# SPDX-FileCopyrightText: 2026 Harald Pretl, Johannes Kepler University
# SPDX-License-Identifier: Apache-2.0 WITH SHL-2.1
# Generated by ip/ez130_8t_decap_hv/scripts/decap_hv_gen.py -- do not edit.

VERSION 5.8 ;
BUSBITCHARS "[]" ;
DIVIDERCHAR "/" ;

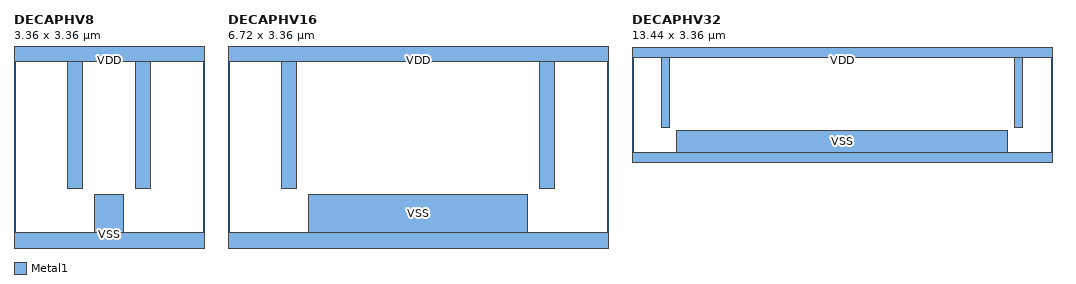
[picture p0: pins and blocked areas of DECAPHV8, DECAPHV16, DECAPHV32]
MACRO DECAPHV8
  CLASS CORE SPACER ;
  ORIGIN 0 0 ;
  FOREIGN DECAPHV8 0 0 ;
  SIZE 3.36 BY 3.36 ;
  SYMMETRY X Y ;
  SITE CoreSite ;
  PIN VDD
    DIRECTION INOUT ;
    USE POWER ;
    SHAPE ABUTMENT ;
    PORT
      LAYER Metal1 ;
        RECT 0 3.2 3.36 3.52 ;
        RECT 0.95 0.95 1.21 3.2 ;
        RECT 2.15 0.95 2.41 3.2 ;
    END
  END VDD
  PIN VSS
    DIRECTION INOUT ;
    USE GROUND ;
    SHAPE ABUTMENT ;
    PORT
      LAYER Metal1 ;
        RECT 0 -0.16 3.36 0.16 ;
        RECT 1.43 0.16 1.93 0.84 ;
    END
  END VSS
END DECAPHV8

MACRO DECAPHV16
  CLASS CORE SPACER ;
  ORIGIN 0 0 ;
  FOREIGN DECAPHV16 0 0 ;
  SIZE 6.72 BY 3.36 ;
  SYMMETRY X Y ;
  SITE CoreSite ;
  PIN VDD
    DIRECTION INOUT ;
    USE POWER ;
    SHAPE ABUTMENT ;
    PORT
      LAYER Metal1 ;
        RECT 0 3.2 6.72 3.52 ;
        RECT 0.95 0.95 1.21 3.2 ;
        RECT 5.51 0.95 5.77 3.2 ;
    END
  END VDD
  PIN VSS
    DIRECTION INOUT ;
    USE GROUND ;
    SHAPE ABUTMENT ;
    PORT
      LAYER Metal1 ;
        RECT 0 -0.16 6.72 0.16 ;
        RECT 1.43 0.16 5.29 0.84 ;
    END
  END VSS
END DECAPHV16

MACRO DECAPHV32
  CLASS CORE SPACER ;
  ORIGIN 0 0 ;
  FOREIGN DECAPHV32 0 0 ;
  SIZE 13.44 BY 3.36 ;
  SYMMETRY X Y ;
  SITE CoreSite ;
  PIN VDD
    DIRECTION INOUT ;
    USE POWER ;
    SHAPE ABUTMENT ;
    PORT
      LAYER Metal1 ;
        RECT 0 3.2 13.44 3.52 ;
        RECT 0.95 0.95 1.21 3.2 ;
        RECT 12.23 0.95 12.49 3.2 ;
    END
  END VDD
  PIN VSS
    DIRECTION INOUT ;
    USE GROUND ;
    SHAPE ABUTMENT ;
    PORT
      LAYER Metal1 ;
        RECT 0 -0.16 13.44 0.16 ;
        RECT 1.43 0.16 12.01 0.84 ;
    END
  END VSS
END DECAPHV32

END LIBRARY
